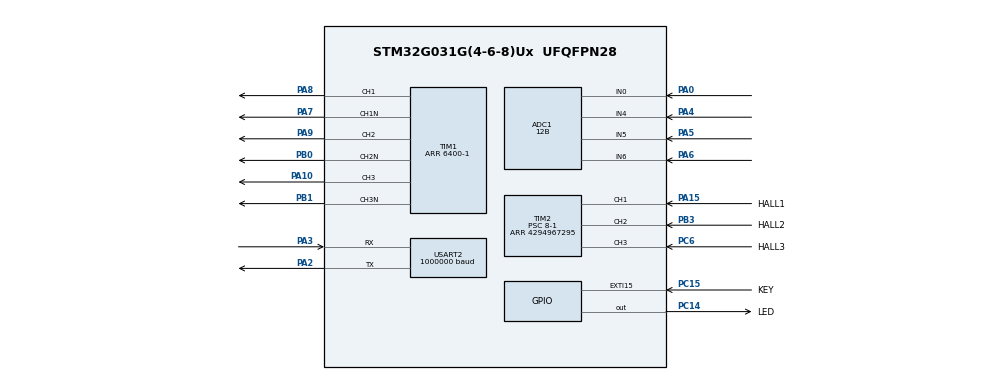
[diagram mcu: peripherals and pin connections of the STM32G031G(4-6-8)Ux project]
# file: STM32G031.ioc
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ADC1.Channel-10\#ChannelRegularConversion=ADC_CHANNEL_6
ADC1.Channel-8\#ChannelRegularConversion=ADC_CHANNEL_4
ADC1.Channel-9\#ChannelRegularConversion=ADC_CHANNEL_5
ADC1.ClockPrescaler=ADC_CLOCK_SYNC_PCLK_DIV2
ADC1.ContinuousConvMode=DISABLE
ADC1.DMAContinuousRequests=DISABLE
ADC1.DiscontinuousConvMode=DISABLE
ADC1.EOCSelection=ADC_EOC_SEQ_CONV
ADC1.EnableAnalogWatchDog1=false
ADC1.ExternalTrigConv=ADC_SOFTWARE_START
ADC1.ExternalTrigConvEdge=ADC_EXTERNALTRIGCONVEDGE_NONE
ADC1.LowPowerAutoPowerOff=DISABLE
ADC1.LowPowerAutoWait=DISABLE
ADC1.NbrOfConversion=3
ADC1.NbrOfConversionFlag=1
ADC1.Overrun=ADC_OVR_DATA_PRESERVED
ADC1.OversamplingMode=DISABLE
ADC1.Rank-10\#ChannelRegularConversion=3
ADC1.Rank-8\#ChannelRegularConversion=1
ADC1.Rank-9\#ChannelRegularConversion=2
ADC1.Resolution=ADC_RESOLUTION_12B
ADC1.SamplingTime-10\#ChannelRegularConversion=ADC_SAMPLINGTIME_COMMON_1
ADC1.SamplingTime-8\#ChannelRegularConversion=ADC_SAMPLINGTIME_COMMON_1
ADC1.SamplingTime-9\#ChannelRegularConversion=ADC_SAMPLINGTIME_COMMON_1
ADC1.SamplingTimeCommon1=ADC_SAMPLETIME_3CYCLES_5
ADC1.SelectedChannel=ADC_CHANNEL_0|ADC_CHANNEL_4|ADC_CHANNEL_5|ADC_CHANNEL_6|ADC_CHANNEL_TEMPSENSOR
ADC1.Sequencer=FULLY_CONFIGURABLE
ADC1.TriggerFrequencyMode=ADC_TRIGGER_FREQ_HIGH
ADC1.master=1
Dma.ADC1.1.Direction=DMA_PERIPH_TO_MEMORY
Dma.ADC1.1.EventEnable=DISABLE
Dma.ADC1.1.Instance=DMA1_Channel1
Dma.ADC1.1.MemDataAlignment=DMA_MDATAALIGN_HALFWORD
Dma.ADC1.1.MemInc=DMA_MINC_ENABLE
Dma.ADC1.1.Mode=DMA_CIRCULAR
Dma.ADC1.1.PeriphDataAlignment=DMA_PDATAALIGN_HALFWORD
Dma.ADC1.1.PeriphInc=DMA_PINC_DISABLE
Dma.ADC1.1.Polarity=HAL_DMAMUX_REQ_GEN_RISING
Dma.ADC1.1.Priority=DMA_PRIORITY_MEDIUM
Dma.ADC1.1.RequestNumber=1
Dma.ADC1.1.SignalID=NONE
Dma.ADC1.1.SyncEnable=DISABLE
Dma.ADC1.1.SyncPolarity=HAL_DMAMUX_SYNC_NO_EVENT
Dma.ADC1.1.SyncRequestNumber=1
Dma.ADC1.1.SyncSignalID=NONE
Dma.Request0=USART2_TX
Dma.Request1=ADC1
Dma.USART2_TX.0.Direction=DMA_MEMORY_TO_PERIPH
Dma.USART2_TX.0.EventEnable=DISABLE
Dma.USART2_TX.0.Instance=DMA1_Channel2
Dma.USART2_TX.0.MemDataAlignment=DMA_MDATAALIGN_BYTE
Dma.USART2_TX.0.MemInc=DMA_MINC_ENABLE
Dma.USART2_TX.0.Mode=DMA_NORMAL
Dma.USART2_TX.0.PeriphDataAlignment=DMA_PDATAALIGN_BYTE
Dma.USART2_TX.0.PeriphInc=DMA_PINC_DISABLE
Dma.USART2_TX.0.Polarity=HAL_DMAMUX_REQ_GEN_RISING
Dma.USART2_TX.0.Priority=DMA_PRIORITY_LOW
Dma.USART2_TX.0.RequestNumber=1
Dma.USART2_TX.0.SignalID=NONE
Dma.USART2_TX.0.SyncEnable=DISABLE
Dma.USART2_TX.0.SyncPolarity=HAL_DMAMUX_SYNC_NO_EVENT
Dma.USART2_TX.0.SyncRequestNumber=1
Dma.USART2_TX.0.SyncSignalID=NONE
Mcu.Family=STM32G0
Mcu.Name=STM32G031G(4-6-8)Ux
Mcu.Package=UFQFPN28
NVIC.ADC1_IRQn=true\:1\:0\:true\:false\:true\:true\:true\:true
NVIC.DMA1_Channel1_IRQn=true\:1\:0\:true\:false\:true\:false\:true\:true
NVIC.DMA1_Channel2_3_IRQn=true\:3\:0\:true\:false\:true\:false\:true\:true
NVIC.EXTI4_15_IRQn=true\:1\:0\:true\:false\:true\:true\:true\:true
NVIC.TIM1_CC_IRQn=true\:0\:0\:true\:false\:true\:true\:true\:true
NVIC.TIM2_IRQn=true\:2\:0\:true\:false\:true\:true\:true\:true
NVIC.USART2_IRQn=true\:3\:0\:true\:false\:true\:true\:true\:true
PA0.Mode=IN0
PA0.Signal=ADC1_IN0
PA10\ [PA12].Signal=S_TIM1_CH3
PA13.Mode=Serial_Wire
PA13.Signal=SYS_SWDIO
PA14-BOOT0.Mode=Serial_Wire
PA14-BOOT0.Signal=SYS_SWCLK
PA15.GPIO_Label=HALL1
PA15.Signal=S_TIM2_CH1_ETR
PA2.Mode=Asynchronous
PA2.Signal=USART2_TX
PA3.Mode=Asynchronous
PA3.Signal=USART2_RX
PA4.Mode=IN4
PA4.Signal=ADC1_IN4
PA5.Mode=IN5
PA5.Signal=ADC1_IN5
PA6.Mode=IN6
PA6.Signal=ADC1_IN6
PA7.Mode=PWM Generation1 CH1 CH1N
PA7.Signal=TIM1_CH1N
PA8.Signal=S_TIM1_CH1
PA9\ [PA11].Signal=S_TIM1_CH2
PB0.Mode=PWM Generation2 CH2 CH2N
PB0.Signal=TIM1_CH2N
PB1.Mode=PWM Generation3 CH3 CH3N
PB1.Signal=TIM1_CH3N
PB3.GPIO_Label=HALL2
PB3.Signal=S_TIM2_CH2
PC14-OSC32_IN\ (PC14).GPIO_Label=LED
PC14-OSC32_IN\ (PC14).GPIO_ModeDefaultOutputPP=GPIO_MODE_OUTPUT_PP
PC14-OSC32_IN\ (PC14).GPIO_PuPd=GPIO_PULLUP
PC14-OSC32_IN\ (PC14).GPIO_Speed=GPIO_SPEED_FREQ_LOW
PC14-OSC32_IN\ (PC14).PinState=GPIO_PIN_SET
PC14-OSC32_IN\ (PC14).Signal=GPIO_Output
PC15-OSC32_OUT\ (PC15).GPIO_Label=KEY
PC15-OSC32_OUT\ (PC15).GPIO_ModeDefaultEXTI=GPIO_MODE_IT_FALLING
PC15-OSC32_OUT\ (PC15).GPIO_PuPd=GPIO_PULLUP
PC15-OSC32_OUT\ (PC15).Signal=GPXTI15
PC6.GPIO_Label=HALL3
PC6.Signal=S_TIM2_CH3
ProjectManager.HeapSize=0x200
ProjectManager.StackSize=0x400
ProjectManager.TargetToolchain=MDK-ARM V5.32
RCC.ADCCLockSelection=RCC_ADCCLKSOURCE_PLLADC
RCC.ADCFreq_Value=64000000
RCC.AHBFreq_Value=64000000
RCC.APB1CLKDivider=RCC_HCLK_DIV2
RCC.CortexFreq_Value=64000000
RCC.EXTERNAL_CLOCK_VALUE=12288000
RCC.HCLKFreq_Value=64000000
RCC.HSE_VALUE=8000000
RCC.HSI_VALUE=16000000
RCC.LSE_VALUE=32768
RCC.PLLM=RCC_PLLM_DIV2
RCC.PLLN=32
RCC.PLLP=RCC_PLLP_DIV4
RCC.PLLQ=RCC_PLLQ_DIV4
RCC.PLLR=RCC_PLLR_DIV4
RCC.SYSCLKFreq_VALUE=64000000
RCC.SYSCLKSource=RCC_SYSCLKSOURCE_PLLCLK
RCC.VCOOutputFreq_Value=256000000
SH.S_TIM1_CH1.0=TIM1_CH1,PWM Generation1 CH1 CH1N
SH.S_TIM1_CH2.0=TIM1_CH2,PWM Generation2 CH2 CH2N
SH.S_TIM1_CH3.0=TIM1_CH3,PWM Generation3 CH3 CH3N
SH.S_TIM2_CH1_ETR.0=TIM2_CH1,Xored_Inputs_Hall_Sensor_Interface
SH.S_TIM2_CH2.0=TIM2_CH2,Xored_Inputs_Hall_Sensor_Interface
SH.S_TIM2_CH3.0=TIM2_CH3,Xored_Inputs_Hall_Sensor_Interface
TIM1.AutoReloadPreload=TIM_AUTORELOAD_PRELOAD_ENABLE
TIM1.Channel-PWM\ Generation1\ CH1\ CH1N=TIM_CHANNEL_1
TIM1.Channel-PWM\ Generation2\ CH2\ CH2N=TIM_CHANNEL_2
TIM1.Channel-PWM\ Generation3\ CH3\ CH3N=TIM_CHANNEL_3
TIM1.Channel-PWM\ Generation4\ No\ Output=TIM_CHANNEL_4
TIM1.ClockDivision=TIM_CLOCKDIVISION_DIV1
TIM1.CounterMode=TIM_COUNTERMODE_CENTERALIGNED1
TIM1.DeadTime=255
TIM1.OCMode_PWM-PWM\ Generation4\ No\ Output=TIM_OCMODE_PWM2
TIM1.OffStateIDLEMode=TIM_OSSI_ENABLE
TIM1.OffStateRunMode=TIM_OSSR_ENABLE
TIM1.Period=6400-1
TIM1.Pulse-PWM\ Generation4\ No\ Output=6400-50
TIM1.RepetitionCounter=1
TIM1.TIM_MasterOutputTrigger=TIM_TRGO_OC4REF
TIM1.TIM_MasterOutputTrigger2=TIM_TRGO2_RESET
TIM1.TIM_MasterSlaveMode=TIM_MASTERSLAVEMODE_DISABLE
TIM2.Commutation_Delay=5
TIM2.IC1Filter=10
TIM2.Period=4294967295
TIM2.Prescaler=8-1
USART2.BaudRate=1000000
USART2.Parity=PARITY_NONE
USART2.VirtualMode-Asynchronous=VM_ASYNC
USART2.WordLength=WORDLENGTH_8B
VP_ADC1_TempSens_Input.Mode=IN-TempSens
VP_CRC_VS_CRC.Mode=CRC_Activate
VP_SYS_VS_PINREMAP.Mode=PINREMAP
VP_SYS_VS_PINREMAP_10_12.Mode=PINREMAP_10_12
VP_TIM1_VS_ClockSourceINT.Mode=Internal
VP_TIM1_VS_no_output4.Mode=PWM Generation4 No Output
VP_TIM2_VS_ClockSourceINT.Mode=Internal
board=custom

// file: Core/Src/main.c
/* USER CODE BEGIN Header */
/**
  ******************************************************************************
  * @file           : main.c
  * @brief          : Main program body
  ******************************************************************************
  * @attention
  *
  * Copyright (c) 2024 STMicroelectronics.
  * All rights reserved.
  *
  * This software is licensed under terms that can be found in the LICENSE file
  * in the root directory of this software component.
  * If no LICENSE file comes with this software, it is provided AS-IS.
  *
  ******************************************************************************
  */
/* USER CODE END Header */
#include "main.h"
#include "adc.h"
#include "crc.h"
#include "dma.h"
#include "tim.h"
#include "usart.h"
#include "gpio.h"

/* USER CODE BEGIN Includes */
#include <stdio.h>
#include "FocCommon.h"
/* USER CODE END Includes */

void SystemClock_Config(void);

/* USER CODE BEGIN 0 */
#define BEAT_CNT 4
const uint16_t beat[BEAT_CNT] = {50, 50, 50, 350};
uint8_t adc_cnt = 0;
/* USER CODE END 0 */

int main(void)
{
  /* USER CODE BEGIN 1 */
	uint16_t cnt = 0;
  /* USER CODE END 1 */

  /* MCU Configuration--------------------------------------------------------*/

  /* Reset of all peripherals, Initializes the Flash interface and the Systick. */
  HAL_Init();

  /* Configure the system clock */
  SystemClock_Config();

  /* Initialize all configured peripherals */
  MX_GPIO_Init();
  MX_DMA_Init();
  MX_TIM1_Init();
  MX_USART2_UART_Init();
  MX_ADC1_Init();
  MX_TIM2_Init();
  MX_CRC_Init();
  /* USER CODE BEGIN 2 */
	TIMx_PWM_Init();
	HAL_TIMEx_HallSensor_Start_IT(&htim2);
  /* USER CODE END 2 */

  /* Infinite loop */
  /* USER CODE BEGIN WHILE */
  while (1)
  {
		HAL_GPIO_TogglePin(LED_GPIO_Port, LED_Pin);
		HAL_Delay(beat[(cnt++)%4]);
    /* USER CODE END WHILE */

  }
}

void SystemClock_Config(void)
{
  RCC_OscInitTypeDef RCC_OscInitStruct = {0};
  RCC_ClkInitTypeDef RCC_ClkInitStruct = {0};

  /** Configure the main internal regulator output voltage
  */
  HAL_PWREx_ControlVoltageScaling(PWR_REGULATOR_VOLTAGE_SCALE1);

  /** Initializes the RCC Oscillators according to the specified parameters
  * in the RCC_OscInitTypeDef structure.
  */
  RCC_OscInitStruct.OscillatorType = RCC_OSCILLATORTYPE_HSI;
  RCC_OscInitStruct.HSIState = RCC_HSI_ON;
  RCC_OscInitStruct.HSIDiv = RCC_HSI_DIV1;
  RCC_OscInitStruct.HSICalibrationValue = RCC_HSICALIBRATION_DEFAULT;
  RCC_OscInitStruct.PLL.PLLState = RCC_PLL_ON;
  RCC_OscInitStruct.PLL.PLLSource = RCC_PLLSOURCE_HSI;
  RCC_OscInitStruct.PLL.PLLM = RCC_PLLM_DIV2;
  RCC_OscInitStruct.PLL.PLLN = 32;
  RCC_OscInitStruct.PLL.PLLP = RCC_PLLP_DIV4;
  RCC_OscInitStruct.PLL.PLLQ = RCC_PLLQ_DIV4;
  RCC_OscInitStruct.PLL.PLLR = RCC_PLLR_DIV2;
  if (HAL_RCC_OscConfig(&RCC_OscInitStruct) != HAL_OK)
  {
    Error_Handler();
  }

  /** Initializes the CPU, AHB and APB buses clocks
  */
  RCC_ClkInitStruct.ClockType = RCC_CLOCKTYPE_HCLK|RCC_CLOCKTYPE_SYSCLK
                              |RCC_CLOCKTYPE_PCLK1;
  RCC_ClkInitStruct.SYSCLKSource = RCC_SYSCLKSOURCE_PLLCLK;
  RCC_ClkInitStruct.AHBCLKDivider = RCC_SYSCLK_DIV1;
  RCC_ClkInitStruct.APB1CLKDivider = RCC_HCLK_DIV2;

  if (HAL_RCC_ClockConfig(&RCC_ClkInitStruct, FLASH_LATENCY_2) != HAL_OK)
  {
    Error_Handler();
  }
}

/* USER CODE BEGIN 4 */

void HAL_TIM_IC_CaptureCallback(TIM_HandleTypeDef *htim) {
	uint32_t captureValue;
    if (htim->Channel == HAL_TIM_ACTIVE_CHANNEL_1) {
        captureValue = HAL_TIM_ReadCapturedValue(&htim2, TIM_CHANNEL_1);
				FOCdata.hall1 = HAL_GPIO_ReadPin(HALL1_GPIO_Port, HALL1_Pin);
    } else if (htim->Channel == HAL_TIM_ACTIVE_CHANNEL_2) {
        captureValue = HAL_TIM_ReadCapturedValue(htim, TIM_CHANNEL_2);
				FOCdata.hall2 = HAL_GPIO_ReadPin(HALL2_GPIO_Port, HALL2_Pin);
    } else if (htim->Channel == HAL_TIM_ACTIVE_CHANNEL_3) {
        captureValue = HAL_TIM_ReadCapturedValue(htim, TIM_CHANNEL_3);
				FOCdata.hall3 = HAL_GPIO_ReadPin(HALL3_GPIO_Port, HALL3_Pin);
    }

		*((uint32_t *)FOCdata.speed) = captureValue;
}

void HAL_ADC_ConvCpltCallback(ADC_HandleTypeDef* hadc){
	if(adc_cnt < 8 )
	{
		ADC_offset[1][0] += ADC_offset[0][0];
		ADC_offset[1][1] += ADC_offset[0][1];
		ADC_offset[1][2] += ADC_offset[0][2];
		adc_cnt++;
		if(adc_cnt >= 8){
			ADC_offset[1][0] /= 8;
			ADC_offset[1][1] /= 8;
			ADC_offset[1][2] /= 8;
			return;
		}
		HAL_ADC_Start_DMA(&ADC_PORT, (uint32_t *)ADC_offset, RESIST_NUM);
	}
}

uint8_t state = 0;
void HAL_GPIO_EXTI_Falling_Callback(uint16_t GPIO_Pin){
	if(GPIO_Pin == KEY_Pin){
		if(state == 0){
			gMotorFOC.SetEnable(1);
			state = 1;
		}
		else {
			gMotorFOC.SetEnable(0);
			state = 0;
		}
	}

}

/* USER CODE END 4 */

void Error_Handler(void)
{
  /* USER CODE BEGIN Error_Handler_Debug */
  /* User can add his own implementation to report the HAL error return state */
  __disable_irq();
	uint32_t error_beat[] = {250,750};
	uint32_t cnt;
  while (1)
  {
		HAL_GPIO_TogglePin(LED_GPIO_Port, LED_Pin);
		HAL_Delay(beat[(cnt++)%2]);
  }
  /* USER CODE END Error_Handler_Debug */
}
